###############################################################
#  Generated by:      Cadence Innovus 25.11-s102_1
#  OS:                Linux x86_64(Host ID ece-linlabsrv01)
#  Generated on:      Wed Mar 18 00:20:02 2026
#  Design:            Core
#  Command:           write_lef_abstract ./output/Core.lef
###############################################################

VERSION 5.8 ;

BUSBITCHARS "[]" ;
DIVIDERCHAR "/" ;

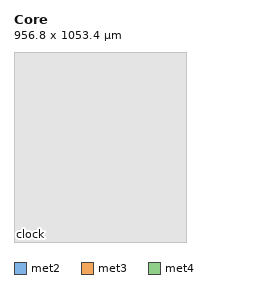
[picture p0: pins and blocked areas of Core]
MACRO Core
  CLASS BLOCK ;
  SIZE 956.800000 BY 1053.400000 ;
  FOREIGN Core 0.000000 0.000000 ;
  ORIGIN 0 0 ;
  SYMMETRY X Y R90 ;
  PIN clock
    DIRECTION INPUT ;
    USE SIGNAL ;
    ANTENNAPARTIALMETALSIDEAREA 2.996 LAYER met2  ;
    ANTENNAPARTIALMETALAREA 0.6636 LAYER met2  ;
    ANTENNAPARTIALCUTAREA 0.08 LAYER via2  ;
    ANTENNAPARTIALMETALSIDEAREA 3.616 LAYER met3  ;
    ANTENNAPARTIALMETALAREA 0.5038 LAYER met3  ;
    ANTENNAPARTIALCUTAREA 0.08 LAYER via3  ;
    ANTENNAPARTIALMETALSIDEAREA 1630.35 LAYER met4  ;
    ANTENNAPARTIALMETALAREA 307.062 LAYER met4  ;
    ANTENNAPARTIALCUTAREA 1.28 LAYER via4  ;
    ANTENNAMODEL OXIDE1 ;
    ANTENNAMAXSIDEAREACAR 299.76 LAYER met5  ;
    ANTENNAMAXAREACAR 91.3949 LAYER met5  ;
    ANTENNAPARTIALMETALSIDEAREA 60 LAYER met5  ;
    ANTENNAPARTIALMETALAREA 29.76 LAYER met5  ;
    ANTENNAGATEAREA 0.567 LAYER met5  ;
    PORT
      LAYER met2 ;
        RECT 0.000000 0.390000 0.485000 0.530000 ;
    END
  END clock
  PIN reset
    DIRECTION INPUT ;
    USE SIGNAL ;
    ANTENNAPARTIALMETALSIDEAREA 18.992 LAYER met3  ;
    ANTENNAPARTIALMETALAREA 3.5642 LAYER met3  ;
    ANTENNAPARTIALCUTAREA 0.08 LAYER via3  ;
    ANTENNAMODEL OXIDE1 ;
    ANTENNAMAXSIDEAREACAR 163.941 LAYER met4  ;
    ANTENNAMAXAREACAR 31.0153 LAYER met4  ;
    ANTENNAPARTIALMETALSIDEAREA 101.76 LAYER met4  ;
    ANTENNAPARTIALMETALAREA 18.9036 LAYER met4  ;
    ANTENNAGATEAREA 1.134 LAYER met4  ;
    PORT
      LAYER met3 ;
        RECT 0.000000 0.470000 0.800000 0.770000 ;
    END
  END reset
  PIN mem_en
    DIRECTION INPUT ;
    USE SIGNAL ;
    ANTENNAPARTIALMETALSIDEAREA 458.256 LAYER met4  ;
    ANTENNAPARTIALMETALAREA 87.4718 LAYER met4  ;
    ANTENNAPARTIALCUTAREA 1.28 LAYER via4  ;
    ANTENNAMODEL OXIDE1 ;
    ANTENNAMAXSIDEAREACAR 527.419 LAYER met5  ;
    ANTENNAMAXAREACAR 115.971 LAYER met5  ;
    ANTENNAPARTIALMETALSIDEAREA 48.432 LAYER met5  ;
    ANTENNAPARTIALMETALAREA 22.048 LAYER met5  ;
    ANTENNAGATEAREA 0.882 LAYER met5  ;
    PORT
      LAYER met4 ;
        RECT 0.000000 0.470000 0.800000 0.770000 ;
    END
  END mem_en
  OBS
    LAYER met1 ;
      RECT 0.000000 0.000000 956.800000 1053.400000 ;
    LAYER met2 ;
      RECT 0.000000 0.670000 956.800000 1053.400000 ;
      RECT 0.625000 0.250000 956.800000 0.670000 ;
      RECT 0.000000 0.000000 956.800000 0.250000 ;
    LAYER met3 ;
      RECT 0.000000 1.070000 956.800000 1053.400000 ;
      RECT 1.100000 0.170000 956.800000 1.070000 ;
      RECT 0.000000 0.000000 956.800000 0.170000 ;
    LAYER met4 ;
      RECT 0.000000 1.070000 956.800000 1053.400000 ;
      RECT 1.100000 0.170000 956.800000 1.070000 ;
      RECT 0.000000 0.000000 956.800000 0.170000 ;
    LAYER met5 ;
      RECT 0.000000 0.000000 956.800000 1053.400000 ;
  END
END Core

END LIBRARY
